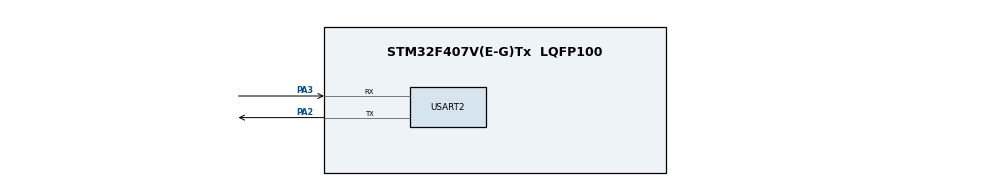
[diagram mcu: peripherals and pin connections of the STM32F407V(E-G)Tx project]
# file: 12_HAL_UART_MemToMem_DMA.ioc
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Dma.MEMTOMEM.0.Direction=DMA_MEMORY_TO_MEMORY
Dma.MEMTOMEM.0.FIFOMode=DMA_FIFOMODE_ENABLE
Dma.MEMTOMEM.0.FIFOThreshold=DMA_FIFO_THRESHOLD_FULL
Dma.MEMTOMEM.0.Instance=DMA2_Stream0
Dma.MEMTOMEM.0.MemBurst=DMA_MBURST_SINGLE
Dma.MEMTOMEM.0.MemDataAlignment=DMA_MDATAALIGN_BYTE
Dma.MEMTOMEM.0.MemInc=DMA_MINC_ENABLE
Dma.MEMTOMEM.0.Mode=DMA_NORMAL
Dma.MEMTOMEM.0.PeriphBurst=DMA_PBURST_SINGLE
Dma.MEMTOMEM.0.PeriphDataAlignment=DMA_PDATAALIGN_BYTE
Dma.MEMTOMEM.0.PeriphInc=DMA_PINC_ENABLE
Dma.MEMTOMEM.0.Priority=DMA_PRIORITY_LOW
Dma.Request0=MEMTOMEM
Mcu.Family=STM32F4
Mcu.Name=STM32F407V(E-G)Tx
Mcu.Package=LQFP100
NVIC.DMA2_Stream0_IRQn=true\:0\:0\:false\:false\:true\:true\:true\:true
NVIC.PriorityGroup=NVIC_PRIORITYGROUP_0
PA2.Mode=Asynchronous
PA2.Signal=USART2_TX
PA3.Mode=Asynchronous
PA3.Signal=USART2_RX
PH0-OSC_IN.Mode=HSE-External-Oscillator
PH0-OSC_IN.Signal=RCC_OSC_IN
PH1-OSC_OUT.Mode=HSE-External-Oscillator
PH1-OSC_OUT.Signal=RCC_OSC_OUT
ProjectManager.HeapSize=0x200
ProjectManager.StackSize=0x400
ProjectManager.TargetToolchain=STM32CubeIDE
RCC.48MHZClocksFreq_Value=48000000
RCC.AHBFreq_Value=168000000
RCC.APB1CLKDivider=RCC_HCLK_DIV4
RCC.APB1Freq_Value=42000000
RCC.APB1TimFreq_Value=84000000
RCC.APB2CLKDivider=RCC_HCLK_DIV2
RCC.APB2Freq_Value=84000000
RCC.APB2TimFreq_Value=168000000
RCC.CortexFreq_Value=168000000
RCC.HCLKFreq_Value=168000000
RCC.HSE_VALUE=8000000
RCC.HSI_VALUE=16000000
RCC.PLLM=8
RCC.PLLN=336
RCC.PLLQ=7
RCC.PLLSourceVirtual=RCC_PLLSOURCE_HSE
RCC.SYSCLKFreq_VALUE=168000000
RCC.SYSCLKSource=RCC_SYSCLKSOURCE_PLLCLK
RCC.VCOOutputFreq_Value=336000000
USART2.VirtualMode=VM_ASYNC
board=STM32F407G-DISC1

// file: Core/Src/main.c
/* USER CODE BEGIN Header */
/**
******************************************************************************
* @file           : main.c
* @brief          : Main program body
******************************************************************************
* @attention
*
* Copyright (c) 2026 STMicroelectronics.
* All rights reserved.
*
* This software is licensed under terms that can be found in the LICENSE file
* in the root directory of this software component.
* If no LICENSE file comes with this software, it is provided AS-IS.
*
******************************************************************************
*/
/* USER CODE END Header */

#include "main.h"

/* USER CODE BEGIN Includes */
#include <string.h>
/* USER CODE END Includes */

UART_HandleTypeDef huart2;

DMA_HandleTypeDef hdma_memtomem_dma2_stream0;

/* USER CODE BEGIN PV */
uint8_t txData[] = "Sethu";
uint8_t rxData[10];
uint8_t txData_UART[20] = "hi hello";
/* USER CODE END PV */

void SystemClock_Config(void);
static void MX_DMA_Init(void);
static void MX_GPIO_Init(void);
static void MX_USART2_UART_Init(void);

/* USER CODE BEGIN PFP */
void My_DMA_Complete(DMA_HandleTypeDef *hdma);
/* USER CODE END PFP */

int main(void)
{

    /* MCU Configuration--------------------------------------------------------*/

    /* Reset of all peripherals, Initializes the Flash interface and the Systick */
    HAL_Init();

    /* Configure the system clock */
    SystemClock_Config();

    /* Initialize all configured peripherals */
    MX_DMA_Init();
    MX_GPIO_Init();
    MX_USART2_UART_Init();

    /* USER CODE BEGIN 2 */

    HAL_StatusTypeDef status;

    hdma_memtomem_dma2_stream0.XferCpltCallback = My_DMA_Complete;

    status = HAL_DMA_Start_IT(&hdma_memtomem_dma2_stream0,
                              (uint32_t)txData,
                              (uint32_t)rxData,
                              strlen((char *)txData) + 1);

    if(status != HAL_OK)
    {
        Error_Handler();
    }

    /* USER CODE END 2 */

    /* Infinite loop */
    while (1)
    {

    }
}

void SystemClock_Config(void)
{
    RCC_OscInitTypeDef RCC_OscInitStruct = {0};
    RCC_ClkInitTypeDef RCC_ClkInitStruct = {0};

    __HAL_RCC_PWR_CLK_ENABLE();
    __HAL_PWR_VOLTAGESCALING_CONFIG(PWR_REGULATOR_VOLTAGE_SCALE1);

    RCC_OscInitStruct.OscillatorType = RCC_OSCILLATORTYPE_HSI;
    RCC_OscInitStruct.HSIState = RCC_HSI_ON;
    RCC_OscInitStruct.HSICalibrationValue = RCC_HSICALIBRATION_DEFAULT;
    RCC_OscInitStruct.PLL.PLLState = RCC_PLL_ON;
    RCC_OscInitStruct.PLL.PLLSource = RCC_PLLSOURCE_HSI;
    RCC_OscInitStruct.PLL.PLLM = 8;
    RCC_OscInitStruct.PLL.PLLN = 50;
    RCC_OscInitStruct.PLL.PLLP = RCC_PLLP_DIV4;
    RCC_OscInitStruct.PLL.PLLQ = 7;

    if(HAL_RCC_OscConfig(&RCC_OscInitStruct) != HAL_OK)
    {
        Error_Handler();
    }

    RCC_ClkInitStruct.ClockType = RCC_CLOCKTYPE_HCLK |
                                  RCC_CLOCKTYPE_SYSCLK |
                                  RCC_CLOCKTYPE_PCLK1 |
                                  RCC_CLOCKTYPE_PCLK2;

    RCC_ClkInitStruct.SYSCLKSource = RCC_SYSCLKSOURCE_PLLCLK;
    RCC_ClkInitStruct.AHBCLKDivider = RCC_SYSCLK_DIV1;
    RCC_ClkInitStruct.APB1CLKDivider = RCC_HCLK_DIV4;
    RCC_ClkInitStruct.APB2CLKDivider = RCC_HCLK_DIV2;

    if(HAL_RCC_ClockConfig(&RCC_ClkInitStruct, FLASH_LATENCY_0) != HAL_OK)
    {
        Error_Handler();
    }
}

static void MX_USART2_UART_Init(void)
{
    huart2.Instance = USART2;
    huart2.Init.BaudRate = 115200;
    huart2.Init.WordLength = UART_WORDLENGTH_8B;
    huart2.Init.StopBits = UART_STOPBITS_1;
    huart2.Init.Parity = UART_PARITY_NONE;
    huart2.Init.Mode = UART_MODE_TX_RX;
    huart2.Init.HwFlowCtl = UART_HWCONTROL_NONE;
    huart2.Init.OverSampling = UART_OVERSAMPLING_16;

    if(HAL_UART_Init(&huart2) != HAL_OK)
    {
        Error_Handler();
    }
}

static void MX_DMA_Init(void)
{
    __HAL_RCC_DMA2_CLK_ENABLE();

    hdma_memtomem_dma2_stream0.Instance = DMA2_Stream0;
    hdma_memtomem_dma2_stream0.Init.Channel = DMA_CHANNEL_0;
    hdma_memtomem_dma2_stream0.Init.Direction = DMA_MEMORY_TO_MEMORY;
    hdma_memtomem_dma2_stream0.Init.PeriphInc = DMA_PINC_ENABLE;
    hdma_memtomem_dma2_stream0.Init.MemInc = DMA_MINC_ENABLE;
    hdma_memtomem_dma2_stream0.Init.PeriphDataAlignment = DMA_PDATAALIGN_BYTE;
    hdma_memtomem_dma2_stream0.Init.MemDataAlignment = DMA_MDATAALIGN_BYTE;
    hdma_memtomem_dma2_stream0.Init.Mode = DMA_NORMAL;
    hdma_memtomem_dma2_stream0.Init.Priority = DMA_PRIORITY_LOW;
    hdma_memtomem_dma2_stream0.Init.FIFOMode = DMA_FIFOMODE_ENABLE;
    hdma_memtomem_dma2_stream0.Init.FIFOThreshold = DMA_FIFO_THRESHOLD_FULL;
    hdma_memtomem_dma2_stream0.Init.MemBurst = DMA_MBURST_SINGLE;
    hdma_memtomem_dma2_stream0.Init.PeriphBurst = DMA_PBURST_SINGLE;

    if(HAL_DMA_Init(&hdma_memtomem_dma2_stream0) != HAL_OK)
    {
        Error_Handler();
    }

    HAL_NVIC_SetPriority(DMA2_Stream0_IRQn, 0, 0);
    HAL_NVIC_EnableIRQ(DMA2_Stream0_IRQn);
}

static void MX_GPIO_Init(void)
{
    GPIO_InitTypeDef GPIO_InitStruct = {0};

    __HAL_RCC_GPIOH_CLK_ENABLE();
    __HAL_RCC_GPIOA_CLK_ENABLE();
    __HAL_RCC_GPIOD_CLK_ENABLE();

    HAL_GPIO_WritePin(GPIOD, GPIO_PIN_13, GPIO_PIN_RESET);

    GPIO_InitStruct.Pin = GPIO_PIN_13;
    GPIO_InitStruct.Mode = GPIO_MODE_OUTPUT_PP;
    GPIO_InitStruct.Pull = GPIO_NOPULL;
    GPIO_InitStruct.Speed = GPIO_SPEED_FREQ_LOW;

    HAL_GPIO_Init(GPIOD, &GPIO_InitStruct);
}

/* USER CODE BEGIN 4 */

void My_DMA_Complete(DMA_HandleTypeDef *hdma)
{
    HAL_GPIO_TogglePin(GPIOD, GPIO_PIN_13);

    HAL_UART_Transmit(&huart2,
                      txData_UART,
                      strlen((char *)txData_UART),
                      HAL_MAX_DELAY);
}

/* USER CODE END 4 */

void Error_Handler(void)
{
    __disable_irq();
    while(1)
    {
    }
}
